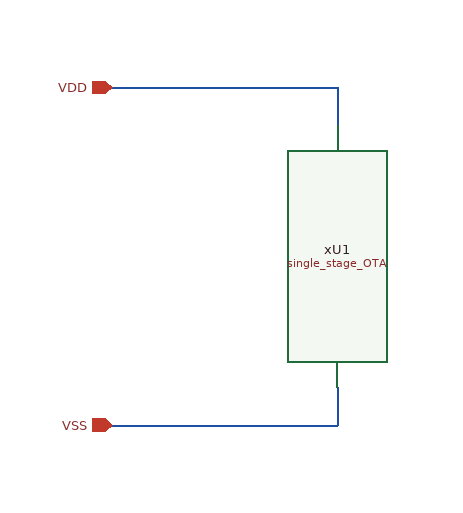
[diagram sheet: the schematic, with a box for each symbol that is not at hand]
v {xschem version=3.4.6 file_version=1.2}
G {}
K {}
V {}
S {}
E {}
N 740 -910 760 -910 {lab=VDD}
N 740 -640 760 -640 {lab=VSS}
N 770 -910 920 -910 {lab=VDD}
N 920 -910 920 -880 {lab=VDD}
N 760 -910 770 -910 {lab=VDD}
N 760 -640 920 -640 {lab=VSS}
N 920 -660 920 -640 {lab=VSS}
N 920 -670 920 -660 {lab=VSS}
C {devices/ipin.sym} 740 -910 0 0 {name=p3 lab=VDD}
C {devices/ipin.sym} 740 -640 0 0 {name=p5 lab=VSS}
C {JNW_BKLE_SKY130A/single_stage_OTA.sym} 870 -780 0 0 {name=xU1}
